VERSION 5.8 ;
BUSBITCHARS "[]" ;
DIVIDERCHAR "/" ;

PROPERTYDEFINITIONS
  LAYER LEF58_TYPE STRING ;
  LAYER LEF58_SPACING STRING ;
  LAYER LEF58_WIDTH STRING ;
END PROPERTYDEFINITIONS

UNITS
  TIME NANOSECONDS 1 ;
  CAPACITANCE PICOFARADS 1 ;
  RESISTANCE OHMS 1 ;
  DATABASE MICRONS 1000 ;
END UNITS
MANUFACTURINGGRID 0.005 ;
LAYER OVERLAP
  TYPE OVERLAP ;
END OVERLAP

LAYER dnwell
  TYPE MASTERSLICE ;
END dnwell

LAYER pwell
  TYPE MASTERSLICE ;
  PROPERTY LEF58_TYPE "TYPE PWELL ;" ;
END pwell

LAYER nwell
  TYPE MASTERSLICE ;
  PROPERTY LEF58_TYPE "TYPE NWELL ;" ;
  PROPERTY LEF58_SPACING "SPACING 1.27 ;" ;
  PROPERTY LEF58_WIDTH "WIDTH 0.84 ;" ;
END nwell

LAYER diff
  TYPE MASTERSLICE ;
  PROPERTY LEF58_TYPE "TYPE DIFFUSION ;" ;
  PROPERTY LEF58_SPACING "SPACING 0.27 ;" ;
  PROPERTY LEF58_WIDTH "WIDTH 0.15 ;" ;
END diff

LAYER tap
  TYPE MASTERSLICE ;
  PROPERTY LEF58_TYPE "TYPE DIFFUSION ;" ;
  PROPERTY LEF58_SPACING "SPACING 0.27 ;" ;
  PROPERTY LEF58_WIDTH "WIDTH 0.15 ;" ;
END tap

LAYER nsdm
  TYPE IMPLANT ;
  WIDTH 0.38 ;
  SPACING 0.38 ;
  AREA 0.265 ;
END nsdm

LAYER psdm
  TYPE IMPLANT ;
  WIDTH 0.38 ;
  SPACING 0.38 ;
  AREA 0.255 ;
END psdm

LAYER poly
  TYPE MASTERSLICE ;
END poly

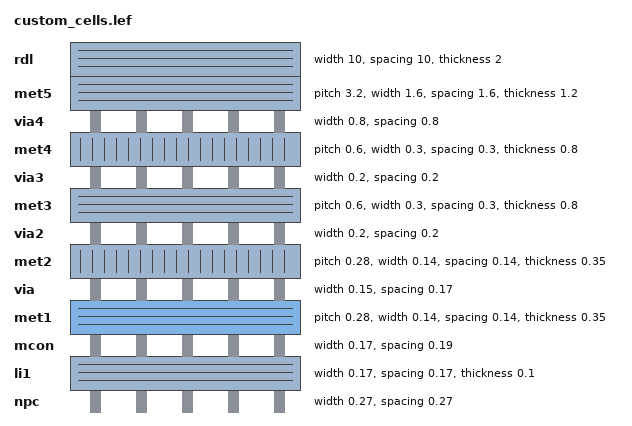
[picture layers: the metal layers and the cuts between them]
LAYER npc
  TYPE CUT ;
  SPACING 0.27 ;
  WIDTH 0.27 ;
  ANTENNAMODEL OXIDE1 ;
END npc

LAYER licon1
  TYPE MASTERSLICE ;
  PROPERTY LEF58_TYPE "TYPE MEOL ;" ;
END licon1

LAYER li1
  TYPE ROUTING ;
  DIRECTION HORIZONTAL ;
  WIDTH 0.17 ;
  AREA 0.056 ;
  SPACING 0.17 ;
  SPACING 0.17 SAMENET ;
  RESISTANCE RPERSQ 12.2 ;
  CAPACITANCE CPERSQDIST 3.69e-05 ;
  THICKNESS 0.1 ;
  EDGECAPACITANCE 3.26e-06 ;
  ANTENNAMODEL OXIDE1 ;
    ANTENNASIDEAREARATIO 75 ;
    ANTENNADIFFSIDEAREARATIO PWL ( ( 0 75 ) ( 0.0125 75 ) ( 0.0225 85.125 ) ( 22.5 10200 ) ) ;
END li1

LAYER mcon
  TYPE CUT ;
  SPACING 0.19 ;
  WIDTH 0.17 ;
  ENCLOSURE BELOW 0 0 ;
  ENCLOSURE ABOVE 0.03 0.06 ;
  ANTENNAMODEL OXIDE1 ;
    ANTENNAAREARATIO 3 ;
    ANTENNADIFFAREARATIO PWL ( ( 0 3 ) ( 0.0125 3 ) ( 0.0225 3.405 ) ( 22.5 408 ) ) ;
  DCCURRENTDENSITY AVERAGE 0.36 ;
END mcon

LAYER met1
  TYPE ROUTING ;
  DIRECTION HORIZONTAL ;
  PITCH 0.28 0.28 ;
  WIDTH 0.14 ;
  OFFSET 0.14 0.14 ;
  AREA 0.083 ;
  SPACING 0.14 ;
  SPACING 0.28 RANGE 3.005 10000 ;
  SPACING 0.14 SAMENET ;
  SPACING 0.28 RANGE 3.005 10000 INFLUENCE 0.28 ;
  MAXWIDTH 4 ;
  MINENCLOSEDAREA 0.14 ;
  RESISTANCE RPERSQ 0.125 ;
  CAPACITANCE CPERSQDIST 2.58e-05 ;
  THICKNESS 0.35 ;
  EDGECAPACITANCE 1.79e-06 ;
  ANTENNAMODEL OXIDE1 ;
    ANTENNASIDEAREARATIO 400 ;
    ANTENNADIFFSIDEAREARATIO PWL ( ( 0 400 ) ( 0.0125 400 ) ( 0.0225 2609 ) ( 22.5 11600 ) ) ;
  ACCURRENTDENSITY RMS 6.1 ;
  DCCURRENTDENSITY AVERAGE 2.8 ;
END met1

LAYER via
  TYPE CUT ;
  SPACING 0.17 ;
  WIDTH 0.15 ;
  ENCLOSURE BELOW 0.055 0.085 ;
  ENCLOSURE ABOVE 0.055 0.085 ;
  ANTENNAMODEL OXIDE1 ;
    ANTENNAAREARATIO 6 ;
    ANTENNADIFFAREARATIO PWL ( ( 0 6 ) ( 0.0125 6 ) ( 0.0225 6.81 ) ( 22.5 816 ) ) ;
  DCCURRENTDENSITY AVERAGE 0.29 ;
END via

LAYER met2
  TYPE ROUTING ;
  DIRECTION VERTICAL ;
  PITCH 0.28 0.28 ;
  WIDTH 0.14 ;
  OFFSET 0.14 0.14 ;
  AREA 0.0676 ;
  SPACING 0.14 ;
  SPACING 0.28 RANGE 3.005 10000 ;
  SPACING 0.14 SAMENET ;
  SPACING 0.28 RANGE 3.005 10000 INFLUENCE 0.28 ;
  MAXWIDTH 4 ;
  MINENCLOSEDAREA 0.14 ;
  RESISTANCE RPERSQ 0.125 ;
  CAPACITANCE CPERSQDIST 1.75e-05 ;
  THICKNESS 0.35 ;
  EDGECAPACITANCE 1.22e-06 ;
  ANTENNAMODEL OXIDE1 ;
    ANTENNASIDEAREARATIO 400 ;
    ANTENNADIFFSIDEAREARATIO PWL ( ( 0 400 ) ( 0.0125 400 ) ( 0.0225 2609 ) ( 22.5 11600 ) ) ;
  ACCURRENTDENSITY RMS 6.1 ;
  DCCURRENTDENSITY AVERAGE 2.8 ;
END met2

LAYER via2
  TYPE CUT ;
  SPACING 0.2 ;
  WIDTH 0.2 ;
  ENCLOSURE BELOW 0.04 0.085 ;
  ENCLOSURE ABOVE 0.065 0.065 ;
  ANTENNAMODEL OXIDE1 ;
    ANTENNAAREARATIO 6 ;
    ANTENNADIFFAREARATIO PWL ( ( 0 6 ) ( 0.0125 6 ) ( 0.0225 6.81 ) ( 22.5 816 ) ) ;
  DCCURRENTDENSITY AVERAGE 0.48 ;
END via2

LAYER met3
  TYPE ROUTING ;
  DIRECTION HORIZONTAL ;
  PITCH 0.6 0.6 ;
  WIDTH 0.3 ;
  OFFSET 0.3 0.3 ;
  AREA 0.24 ;
  SPACING 0.3 ;
  SPACING 0.4 RANGE 3.005 10000 ;
  SPACING 0.3 SAMENET ;
  SPACING 0.4 RANGE 3.005 10000 INFLUENCE 0.4 ;
  MAXWIDTH 4 ;
  MINENCLOSEDAREA 0.2 ;
  RESISTANCE RPERSQ 0.047 ;
  CAPACITANCE CPERSQDIST 1.26e-05 ;
  THICKNESS 0.8 ;
  EDGECAPACITANCE 1.86e-06 ;
  ANTENNAMODEL OXIDE1 ;
    ANTENNASIDEAREARATIO 400 ;
    ANTENNADIFFSIDEAREARATIO PWL ( ( 0 400 ) ( 0.0125 400 ) ( 0.0225 2609 ) ( 22.5 11600 ) ) ;
  ACCURRENTDENSITY RMS 14.9 ;
  DCCURRENTDENSITY AVERAGE 6.8 ;
END met3

LAYER via3
  TYPE CUT ;
  SPACING 0.2 ;
  WIDTH 0.2 ;
  ENCLOSURE BELOW 0.06 0.09 ;
  ENCLOSURE ABOVE 0.065 0.065 ;
  ANTENNAMODEL OXIDE1 ;
    ANTENNAAREARATIO 6 ;
    ANTENNADIFFAREARATIO PWL ( ( 0 6 ) ( 0.0125 6 ) ( 0.0225 6.81 ) ( 22.5 816 ) ) ;
  DCCURRENTDENSITY AVERAGE 0.48 ;
END via3

LAYER met4
  TYPE ROUTING ;
  DIRECTION VERTICAL ;
  PITCH 0.6 0.6 ;
  WIDTH 0.3 ;
  OFFSET 0.3 0.3 ;
  AREA 0.24 ;
  SPACING 0.3 ;
  SPACING 0.4 RANGE 3.005 10000 ;
  SPACING 0.3 SAMENET ;
  SPACING 0.4 RANGE 3.005 10000 INFLUENCE 0.4 ;
  MAXWIDTH 10 ;
  MINENCLOSEDAREA 0.2 ;
  RESISTANCE RPERSQ 0.047 ;
  CAPACITANCE CPERSQDIST 8.67e-06 ;
  THICKNESS 0.8 ;
  EDGECAPACITANCE 1.29e-06 ;
  ANTENNAMODEL OXIDE1 ;
    ANTENNASIDEAREARATIO 400 ;
    ANTENNADIFFSIDEAREARATIO PWL ( ( 0 400 ) ( 0.0125 400 ) ( 0.0225 2609 ) ( 22.5 11600 ) ) ;
  ACCURRENTDENSITY RMS 14.9 ;
  DCCURRENTDENSITY AVERAGE 6.8 ;
END met4

LAYER via4
  TYPE CUT ;
  SPACING 0.8 ;
  WIDTH 0.8 ;
  ENCLOSURE BELOW 0.19 0.19 ;
  ENCLOSURE ABOVE 0.31 0.31 ;
  ANTENNAMODEL OXIDE1 ;
    ANTENNAAREARATIO 6 ;
    ANTENNADIFFAREARATIO PWL ( ( 0 6 ) ( 0.0125 6 ) ( 0.0225 6.81 ) ( 22.5 816 ) ) ;
  DCCURRENTDENSITY AVERAGE 2.49 ;
END via4

LAYER met5
  TYPE ROUTING ;
  DIRECTION HORIZONTAL ;
  PITCH 3.2 3.2 ;
  WIDTH 1.6 ;
  OFFSET 1.6 1.6 ;
  AREA 4 ;
  SPACING 1.6 ;
  SPACING 1.6 SAMENET ;
  RESISTANCE RPERSQ 0.0285 ;
  CAPACITANCE CPERSQDIST 6.48e-06 ;
  THICKNESS 1.2 ;
  EDGECAPACITANCE 4.96e-06 ;
  ANTENNAMODEL OXIDE1 ;
    ANTENNASIDEAREARATIO 400 ;
    ANTENNADIFFSIDEAREARATIO PWL ( ( 0 400 ) ( 0.0125 400 ) ( 0.0225 2609 ) ( 22.5 11600 ) ) ;
  ACCURRENTDENSITY RMS 22.34 ;
  DCCURRENTDENSITY AVERAGE 10.17 ;
END met5

LAYER rdl
  TYPE ROUTING ;
  DIRECTION HORIZONTAL ;
  WIDTH 10 ;
  SPACING 10 ;
  RESISTANCE RPERSQ 0.005 ;
  CAPACITANCE CPERSQDIST 2.66e-06 ;
  THICKNESS 2 ;
  EDGECAPACITANCE 6.2e-06 ;
  ANTENNAMODEL OXIDE1 ;
END rdl

VIARULE M4M5_C GENERATE DEFAULT
  LAYER met5 ;
    ENCLOSURE 0.31 0.31 ;
  LAYER met4 ;
    ENCLOSURE 0.19 0.19 ;
  LAYER via4 ;
    RECT -0.4 -0.4 0.4 0.4 ;
    SPACING 1.6 BY 1.6 ;
    RESISTANCE 0.380000 ;
END M4M5_C

VIARULE M3M4_C GENERATE DEFAULT
  LAYER met4 ;
    ENCLOSURE 0.065 0.065 ;
  LAYER met3 ;
    ENCLOSURE 0.06 0.09 ;
  LAYER via3 ;
    RECT -0.1 -0.1 0.1 0.1 ;
    SPACING 0.4 BY 0.4 ;
    RESISTANCE 3.410000 ;
END M3M4_C

VIARULE M2M3_C GENERATE DEFAULT
  LAYER met3 ;
    ENCLOSURE 0.065 0.065 ;
  LAYER met2 ;
    ENCLOSURE 0.04 0.085 ;
  LAYER via2 ;
    RECT -0.1 -0.1 0.1 0.1 ;
    SPACING 0.4 BY 0.4 ;
    RESISTANCE 3.410000 ;
END M2M3_C

VIARULE M1M2_C GENERATE DEFAULT
  LAYER met2 ;
    ENCLOSURE 0.055 0.085 ;
  LAYER met1 ;
    ENCLOSURE 0.055 0.085 ;
  LAYER via ;
    RECT -0.075 -0.075 0.075 0.075 ;
    SPACING 0.32 BY 0.32 ;
    RESISTANCE 4.500000 ;
END M1M2_C

VIARULE L1M1_C GENERATE DEFAULT
  LAYER met1 ;
    ENCLOSURE 0.03 0.06 ;
  LAYER li1 ;
    ENCLOSURE 0 0.08 ;
  LAYER mcon ;
    RECT -0.085 -0.085 0.085 0.085 ;
    SPACING 0.36 BY 0.36 ;
    RESISTANCE 9.300000 ;
END L1M1_C

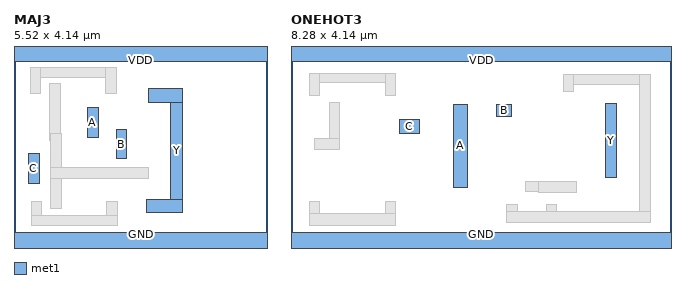
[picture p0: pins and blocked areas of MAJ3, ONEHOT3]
MACRO MAJ3
  CLASS CORE ;
  ORIGIN 0 0 ;
  FOREIGN MAJ3 0 0 ;
  SIZE 5.52 BY 4.14 ;
  SYMMETRY X Y ;
  SITE CoreSite ;
  PIN GND
    DIRECTION INOUT ;
    USE GROUND ;
    SHAPE ABUTMENT ;
    PORT
      LAYER met1 ;
        RECT 0 -0.2 5.52 0.205 ;
    END
  END GND
  PIN C
    DIRECTION INPUT ;
    USE SIGNAL ;
    PORT
      LAYER met1 ;
        RECT 0.315 1.27 0.545 1.93 ;
    END
  END C
  PIN B
    DIRECTION INPUT ;
    USE SIGNAL ;
    PORT
      LAYER met1 ;
        RECT 2.225 1.81 2.455 2.455 ;
    END
  END B
  PIN A
    DIRECTION INPUT ;
    USE SIGNAL ;
    PORT
      LAYER met1 ;
        RECT 1.605 2.28 1.835 2.935 ;
    END
  END A
  PIN Y
    DIRECTION OUTPUT ;
    USE SIGNAL ;
    PORT
      LAYER met1 ;
        RECT 2.92 3.05 3.675 3.35 ;
        RECT 3.41 0.645 3.675 3.35 ;
        RECT 2.885 0.645 3.675 0.935 ;
    END
  END Y
  PIN VDD
    DIRECTION INOUT ;
    USE POWER ;
    SHAPE ABUTMENT ;
    PORT
      LAYER met1 ;
        RECT 0 3.94 5.52 4.34 ;
    END
  END VDD
  OBS
    LAYER mcon ;
      RECT 4.165 4.055 4.335 4.225 ;
      RECT 4.145 -0.09 4.315 0.08 ;
      RECT 3.805 4.055 3.975 4.225 ;
      RECT 3.785 -0.09 3.955 0.08 ;
      RECT 3.445 4.055 3.615 4.225 ;
      RECT 3.425 -0.09 3.595 0.08 ;
      RECT 3.085 4.055 3.255 4.225 ;
      RECT 3.065 -0.09 3.235 0.08 ;
      RECT 2.95 3.12 3.12 3.29 ;
      RECT 2.915 0.705 3.085 0.875 ;
      RECT 2.725 4.055 2.895 4.225 ;
      RECT 2.71 1.415 2.88 1.585 ;
      RECT 2.705 -0.09 2.875 0.08 ;
      RECT 2.365 4.055 2.535 4.225 ;
      RECT 2.345 -0.09 2.515 0.08 ;
      RECT 2.255 1.87 2.425 2.04 ;
      RECT 2.055 0.66 2.225 0.83 ;
      RECT 2.03 3.305 2.2 3.475 ;
      RECT 2.005 4.055 2.175 4.225 ;
      RECT 1.985 -0.09 2.155 0.08 ;
      RECT 1.645 4.055 1.815 4.225 ;
      RECT 1.635 2.705 1.805 2.875 ;
      RECT 1.625 -0.09 1.795 0.08 ;
      RECT 1.285 4.055 1.455 4.225 ;
      RECT 1.265 -0.09 1.435 0.08 ;
      RECT 0.925 4.055 1.095 4.225 ;
      RECT 0.905 -0.09 1.075 0.08 ;
      RECT 0.835 0.78 1.005 0.95 ;
      RECT 0.81 3.215 0.98 3.385 ;
      RECT 0.565 4.055 0.735 4.225 ;
      RECT 0.545 -0.09 0.715 0.08 ;
      RECT 0.405 0.66 0.575 0.83 ;
      RECT 0.38 3.305 0.55 3.475 ;
      RECT 0.345 1.33 0.515 1.5 ;
      RECT 0.205 4.055 0.375 4.225 ;
      RECT 0.185 -0.09 0.355 0.08 ;
    LAYER met1 ;
      RECT 0.78 2.215 1.01 3.445 ;
      RECT 0.805 0.72 1.035 2.36 ;
      RECT 0.805 1.385 2.94 1.615 ;
      RECT 2.025 0.37 2.255 0.89 ;
      RECT 0.375 0.37 0.605 0.89 ;
      RECT 0.375 0.37 2.255 0.575 ;
      RECT 0.35 3.595 2.23 3.8 ;
      RECT 2 3.245 2.23 3.8 ;
      RECT 0.35 3.245 0.58 3.8 ;
  END
END MAJ3

MACRO ONEHOT3
  CLASS CORE ;
  ORIGIN 0 0 ;
  FOREIGN ONEHOT3 0 0 ;
  SIZE 8.28 BY 4.14 ;
  SYMMETRY X Y ;
  SITE CoreSite ;
  PIN GND
    DIRECTION INOUT ;
    USE GROUND ;
    SHAPE ABUTMENT ;
    PORT
      LAYER met1 ;
        RECT 0 -0.2 8.28 0.2 ;
    END
  END GND
  PIN C
    DIRECTION INPUT ;
    USE SIGNAL ;
    PORT
      LAYER met1 ;
        RECT 2.36 2.365 2.805 2.66 ;
    END
  END C
  PIN B
    DIRECTION INPUT ;
    USE SIGNAL ;
    PORT
      LAYER met1 ;
        RECT 4.48 2.725 4.81 2.995 ;
    END
  END B
  PIN A
    DIRECTION INPUT ;
    USE SIGNAL ;
    PORT
      LAYER met1 ;
        RECT 3.545 1.195 3.84 3 ;
    END
  END A
  PIN Y
    DIRECTION OUTPUT ;
    USE SIGNAL ;
    PORT
      LAYER met1 ;
        RECT 6.855 1.4 7.085 3.015 ;
    END
  END Y
  PIN VDD
    DIRECTION INOUT ;
    USE POWER ;
    SHAPE ABUTMENT ;
    PORT
      LAYER met1 ;
        RECT 0 3.94 8.28 4.34 ;
    END
  END VDD
  OBS
    LAYER mcon ;
      RECT 7.625 2.135 7.795 2.305 ;
      RECT 7.05 4.055 7.22 4.225 ;
      RECT 7.025 -0.085 7.195 0.085 ;
      RECT 6.885 1.46 7.055 1.63 ;
      RECT 6.885 2.785 7.055 2.955 ;
      RECT 6.69 4.055 6.86 4.225 ;
      RECT 6.665 -0.085 6.835 0.085 ;
      RECT 6.33 4.055 6.5 4.225 ;
      RECT 6.305 -0.085 6.475 0.085 ;
      RECT 6 1.115 6.17 1.285 ;
      RECT 5.97 4.055 6.14 4.225 ;
      RECT 5.965 3.335 6.135 3.505 ;
      RECT 5.945 -0.085 6.115 0.085 ;
      RECT 5.61 4.055 5.78 4.225 ;
      RECT 5.595 0.595 5.765 0.765 ;
      RECT 5.585 -0.085 5.755 0.085 ;
      RECT 5.25 4.055 5.42 4.225 ;
      RECT 5.225 -0.085 5.395 0.085 ;
      RECT 5.17 1.12 5.34 1.29 ;
      RECT 4.89 4.055 5.06 4.225 ;
      RECT 4.865 -0.085 5.035 0.085 ;
      RECT 4.735 0.59 4.905 0.76 ;
      RECT 4.56 2.775 4.73 2.945 ;
      RECT 4.53 4.055 4.7 4.225 ;
      RECT 4.505 -0.085 4.675 0.085 ;
      RECT 4.17 4.055 4.34 4.225 ;
      RECT 4.145 -0.085 4.315 0.085 ;
      RECT 3.81 4.055 3.98 4.225 ;
      RECT 3.785 -0.085 3.955 0.085 ;
      RECT 3.61 1.225 3.78 1.395 ;
      RECT 3.605 2.8 3.775 2.97 ;
      RECT 3.45 4.055 3.62 4.225 ;
      RECT 3.425 -0.085 3.595 0.085 ;
      RECT 3.09 4.055 3.26 4.225 ;
      RECT 3.065 -0.085 3.235 0.085 ;
      RECT 2.73 4.055 2.9 4.225 ;
      RECT 2.705 -0.085 2.875 0.085 ;
      RECT 2.575 2.395 2.745 2.565 ;
      RECT 2.37 4.055 2.54 4.225 ;
      RECT 2.345 -0.085 2.515 0.085 ;
      RECT 2.08 0.655 2.25 0.825 ;
      RECT 2.08 3.255 2.25 3.425 ;
      RECT 2.01 4.055 2.18 4.225 ;
      RECT 1.985 -0.085 2.155 0.085 ;
      RECT 1.65 4.055 1.82 4.225 ;
      RECT 1.625 -0.085 1.795 0.085 ;
      RECT 1.29 4.055 1.46 4.225 ;
      RECT 1.265 -0.085 1.435 0.085 ;
      RECT 0.93 4.055 1.1 4.225 ;
      RECT 0.905 -0.085 1.075 0.085 ;
      RECT 0.86 2.82 1.03 2.99 ;
      RECT 0.58 2.055 0.75 2.225 ;
      RECT 0.57 4.055 0.74 4.225 ;
      RECT 0.545 -0.085 0.715 0.085 ;
      RECT 0.43 0.655 0.6 0.825 ;
      RECT 0.43 3.255 0.6 3.425 ;
      RECT 0.21 4.055 0.38 4.225 ;
      RECT 0.185 -0.085 0.355 0.085 ;
    LAYER met1 ;
      RECT 5.935 3.435 7.84 3.66 ;
      RECT 7.59 0.43 7.84 3.66 ;
      RECT 5.935 3.275 6.165 3.66 ;
      RECT 5.565 0.43 5.795 0.825 ;
      RECT 4.705 0.43 4.935 0.82 ;
      RECT 4.705 0.43 7.84 0.665 ;
      RECT 5.11 1.09 6.23 1.32 ;
      RECT 5.4 1.085 6.23 1.32 ;
      RECT 2.05 0.37 2.28 0.885 ;
      RECT 0.4 0.37 0.63 0.885 ;
      RECT 0.4 0.37 2.28 0.615 ;
      RECT 0.4 3.475 2.28 3.675 ;
      RECT 2.05 3.195 2.28 3.675 ;
      RECT 0.4 3.195 0.63 3.675 ;
      RECT 0.83 2.025 1.06 3.05 ;
      RECT 0.52 2.025 1.06 2.255 ;
  END
END ONEHOT3

END LIBRARY
